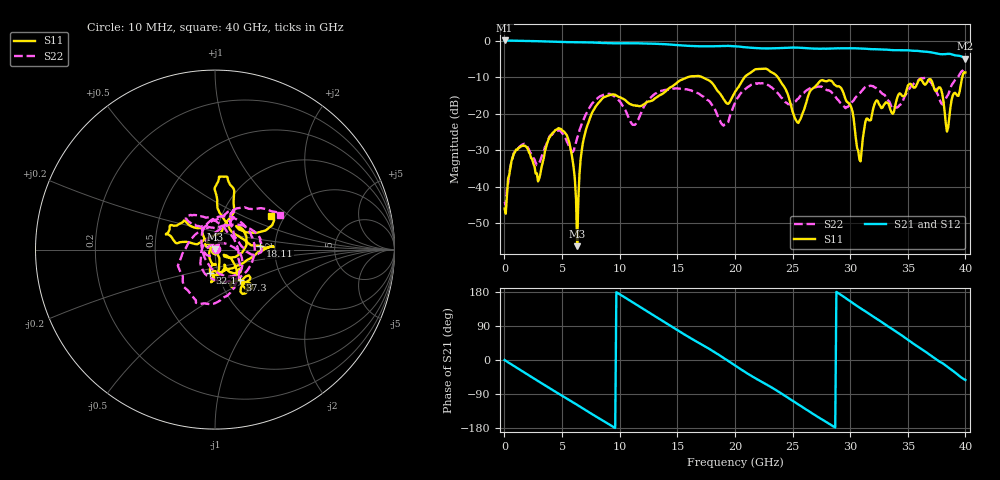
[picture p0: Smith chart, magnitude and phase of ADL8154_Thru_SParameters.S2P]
! Analog Devices, Inc."
! Device:	ADL8154ACPZN - THRU
! Description:	"10 MHz to 6 GHz, Wideband, Low Noise Amplifier"
! Conditions:	Pin = -25 dBm
!		Operating Temperature = +25 C (at package bottom)
! Measurement used thru-cal line of SN#48.
! Frequency (GHz)	S11_Mag (dB)	S11_Phase (deg)	S21_Mag (dB)	S21_Phase (deg)	S12_Mag (dB)	S12_Phase (deg)	S22_Mag (dB)	S22_Phase (deg)
#  GHZ  S  DB  R 50
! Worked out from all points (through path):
!   401 points, 10 MHz to 40 GHz, reference 50 ohm
!   highest |S21| = 0.01 dB at 10 MHz (marker M1); lowest = -5.0 dB at 40 GHz (marker M2)
!   group delay of S21, straight-line fit = 53 ps
!   lowest |S11| = -56.3 dB at 6.308 GHz (marker M3), VSWR 1.00, Z = 50 + j0.147 ohm
!   |S11| at or under -10 dB: start of sweep to 15.94 GHz; 17.14 GHz to 20.86 GHz (3.717 GHz wide, 19.6 % of centre); 23.71 GHz to 39.73 GHz (16.03 GHz wide, 50.5 % of centre)
!   |S22| runs from -45.1 to -7.7 dB; largest |S21 - S12| = 0.0065
!   S11 on the Smith chart (normalised r, x): 10 MHz: 1.00, -0.01; 18.11 GHz: 1.67, +0.07; 32.1 GHz: 0.92, -0.24; 37.3 GHz: 1.24, -0.44; 40 GHz: 1.71, +0.74
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0.01  -45.99 -119.6  0.01 -0.0  0.01 0.1  -44.14 8.2
1.01  -29.83 66.0  -0.07 -19.5  -0.07 -19.5  -29.82 60.5
2.909  -38.55 106.3  -0.19 -55.5  -0.19 -55.5  -34.01 -44.3
4.709  -23.97 153.6  -0.40 -89.0  -0.41 -89.0  -24.59 -162.6
5.609  -27.71 139.9  -0.45 -105.5  -0.45 -105.5  -28.93 145.3
6.308  -56.27 72.6  -0.47 -118.4  -0.47 -118.5  -26.68 54.8
6.708  -29.99 -62.8  -0.48 -126.0  -0.49 -126.1  -22.79 25.7
8.608  -15.53 -90.8  -0.68 -161.3  -0.69 -161.4  -14.83 -34.3
11.207  -17.75 -76.7  -0.75 150.8  -0.75 150.8  -23.08 -161.5
13.407  -15.10 -24.6  -0.94 109.0  -0.94 109.0  -13.88 67.9
18.105  -11.94 4.4  -1.58 23.2  -1.58 23.2  -18.10 -127.3
20.005  -14.08 80.3  -1.57 -14.4  -1.57 -14.4  -17.05 66.2
22.804  -7.87 80.0  -2.18 -65.7  -2.18 -65.9  -12.07 -4.1
25.504  -22.57 119.8  -1.96 -117.6  -1.96 -117.7  -15.93 55.4
26.703  -13.26 170.6  -2.18 -140.9  -2.17 -141.0  -13.03 65.4
29.203  -12.95 136.1  -2.13 171.7  -2.13 171.6  -17.15 73.0
30.802  -32.62 135.3  -2.20 138.5  -2.20 138.3  -14.55 131.9
32.102  -17.49 -101.8  -2.37 112.8  -2.39 112.7  -12.80 123.6
33.402  -18.01 -68.8  -2.56 86.5  -2.60 86.4  -16.70 76.6
37.301  -13.23 -50.1  -3.40 4.9  -3.40 4.8  -12.81 -148.4
38.4  -24.93 -30.5  -3.67 -17.1  -3.69 -17.1  -15.27 83.8
40  -8.73 30.9  -4.99 -52.7  -5.02 -53.0  -7.68 27.9
